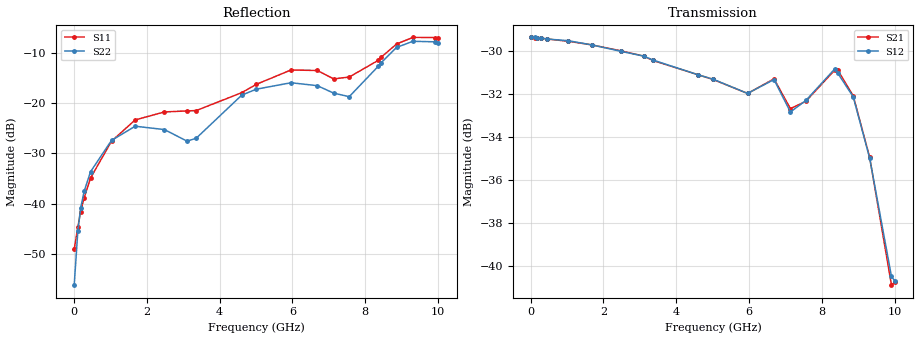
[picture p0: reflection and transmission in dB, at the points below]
! Device ID: PE43704
! Dir: z:\PE43704\PE43704_Char_1_20130516\PE43704\AMB\3p400V\28p50dB
! Serial: 14
! Insertion: A
! Impedance: 50 ohm
! Temp: Amb
! VDD: 3.400V
! Attenuation Step: 28.50dB
! IDD: 1.139780e-01mA
#  Hz  S  RI  R  50
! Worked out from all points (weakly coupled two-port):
!   401 points, 10 MHz to 10.01 GHz, reference 50 ohm
!   highest |S21| = -29.37 dB at 10 MHz (marker M1); lowest = -40.9 dB at 9.91 GHz (marker M2)
!   lowest |S11| = -49.0 dB at 10 MHz (marker M3), VSWR 1.01, Z = 50.4 + j0.0402 ohm
!   |S11| at or under -10 dB: start of sweep to 8.565 GHz
!   |S22| runs from -56.1 to -7.6 dB; largest |S21 - S12| = 0.00062
!   S11 on the Smith chart (normalised r, x): 10 MHz: 1.01, +0.00; 4.61 GHz: 0.79, +0.08; 8.435 GHz: 0.76, +0.46; 9.31 GHz: 0.51, +0.52; 10.01 GHz: 0.44, +0.31
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1e7  0.00351 0.000399  0.034 -8.02e-05  0.034 -8.51e-05  -0.00149 0.000456
1.1e8  0.00344 0.00471  0.0339 -0.000974  0.034 -0.000936  -0.00154 0.00514
1.85e8  0.00263 0.00796  0.0339 -0.00156  0.0339 -0.00156  -0.00208 0.00874
2.85e8  0.000603 0.0115  0.0338 -0.00239  0.0338 -0.00236  -0.00385 0.0128
4.6e8  -0.0045 0.0175  0.0335 -0.00378  0.0335 -0.00377  -0.00864 0.019
1.035e9  -0.0346 0.0236  0.0323 -0.00817  0.0324 -0.00817  -0.0344 0.0251
1.685e9  -0.0677 0.00661  0.0301 -0.0127  0.0301 -0.0127  -0.0583 0.00813
2.485e9  -0.0798 -0.0169  0.0265 -0.0173  0.0264 -0.0173  -0.0541 -0.00715
3.11e9  -0.0818 -0.017  0.0232 -0.0202  0.0232 -0.0202  -0.0417 0.00331
3.36e9  -0.0835 -0.0107  0.0215 -0.021  0.0217 -0.0209  -0.0431 0.012
4.61e9  -0.1166 0.0499  0.0149 -0.0235  0.0149 -0.0235  -0.1022 0.0626
5.01e9  -0.1358 0.0712  0.0136 -0.0235  0.0135 -0.0236  -0.1229 0.0611
5.96e9  -0.1864 0.1029  0.0088 -0.0236  0.00882 -0.0236  -0.1485 0.0569
6.685e9  -0.1872 0.0962  0.00709 -0.0263  0.00668 -0.0263  -0.1384 0.0545
7.135e9  -0.1545 0.0794  0.00238 -0.0231  0.00224 -0.0227  -0.1043 0.0695
7.56e9  -0.1296 0.1266  0.00272 -0.024  0.00277 -0.0241  -0.0695 0.0925
8.36e9  -0.0592 0.259  -0.00582 -0.028  -0.0057 -0.0282  -0.0776 0.2189
8.435e9  -0.0607 0.2782  -0.00733 -0.0276  -0.00698 -0.0272  -0.086 0.2358
8.86e9  -0.1007 0.3722  -0.013 -0.0212  -0.0129 -0.0211  -0.1433 0.3263
9.31e9  -0.1825 0.4097  -0.0121 -0.0132  -0.0121 -0.0131  -0.2275 0.3414
9.91e9  -0.3114 0.3209  -0.00349 -0.00832  -0.00381 -0.00865  -0.3455 0.2118
1.001e10  -0.3287 0.2884  -0.00201 -0.00896  -0.00185 -0.00902  -0.3582 0.1751
